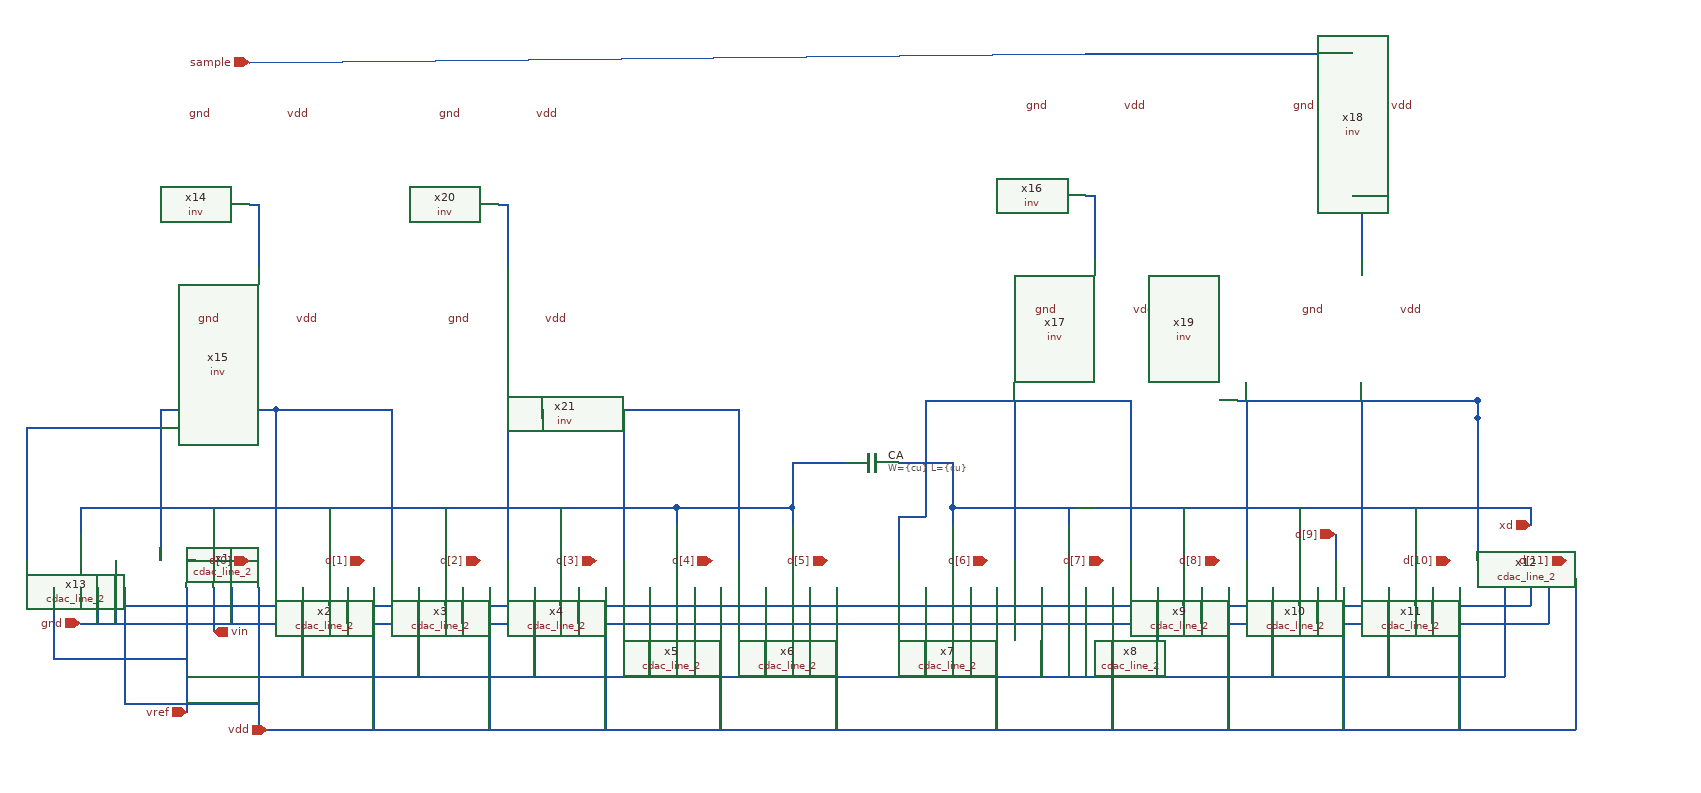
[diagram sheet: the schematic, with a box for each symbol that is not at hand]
v {xschem version=3.4.4 file_version=1.2
}
G {}
K {}
V {}
S {}
E {}
N 80 -160 80 -140 {
lab=#net1}
N -70 -160 -70 -130 {
lab=#net1}
N 50 -100 60 -100 {
lab=#net2}
N 210 -160 210 -140 {
lab=#net1}
N 340 -160 340 -140 {
lab=#net1}
N 470 -160 470 -140 {
lab=#net1}
N 600 -160 600 -140 {
lab=#net1}
N 730 -160 730 -140 {
lab=#net1}
N 910 -160 910 -140 {
lab=xd}
N 1040 -160 1040 -140 {
lab=xd}
N 1170 -160 1170 -140 {
lab=xd}
N 1300 -160 1300 -140 {
lab=xd}
N 1430 -160 1430 -140 {
lab=xd}
N 80 -70 80 -40 {
lab=vin}
N 210 -70 210 -50 {
lab=vin}
N 80 -40 80 -20 {
lab=vin}
N 230 -70 230 -30 {
lab=gnd}
N 1560 -70 1560 -50 {
lab=vin}
N 1430 -70 1430 -50 {
lab=vin}
N 1300 -70 1300 -50 {
lab=vin}
N 1170 -70 1170 -50 {
lab=vin}
N 1040 -70 1040 -50 {
lab=vin}
N 910 -70 910 -50 {
lab=vin}
N 730 -70 730 -50 {
lab=vin}
N 600 -70 600 -50 {
lab=vin}
N 470 -70 470 -50 {
lab=vin}
N 340 -70 340 -50 {
lab=vin}
N 1580 -70 1580 -30 {
lab=gnd}
N 1450 -70 1450 -30 {
lab=gnd}
N 1320 -70 1320 -30 {
lab=gnd}
N 1190 -70 1190 -30 {
lab=gnd}
N 1060 -70 1060 -30 {
lab=gnd}
N 930 -70 930 -30 {
lab=gnd}
N 750 -70 750 -30 {
lab=gnd}
N 620 -70 620 -30 {
lab=gnd}
N 490 -70 490 -30 {
lab=gnd}
N 360 -70 360 -30 {
lab=gnd}
N -70 -30 1580 -30 {
lab=gnd}
N 730 -210 730 -160 {
lab=#net1}
N 850 -210 910 -210 {
lab=xd}
N 910 -210 910 -160 {
lab=xd}
N 80 -50 1560 -50 {
lab=vin}
N 100 -70 100 -30 {
lab=gnd}
N 1040 -160 1560 -160 {
lab=xd}
N 910 -160 1050 -160 {
lab=xd}
N 50 -70 50 70 {
lab=vref}
N 180 -70 180 20 {
lab=vref}
N 310 -70 310 20 {
lab=vref}
N 440 -70 440 20 {
lab=vref}
N 570 -70 570 20 {
lab=vref}
N 700 -70 700 20 {
lab=vref}
N 880 -70 880 30 {
lab=vref}
N 1010 -70 1010 30 {
lab=vref}
N 1140 -70 1140 30 {
lab=vref}
N 1270 -70 1270 30 {
lab=vref}
N 1400 -70 1400 30 {
lab=vref}
N 1530 -70 1530 30 {
lab=vref}
N 50 30 1530 30 {
lab=vref}
N 570 20 570 30 {
lab=vref}
N 700 20 700 30 {
lab=vref}
N 440 20 440 30 {
lab=vref}
N 310 20 310 30 {
lab=vref}
N 180 20 180 30 {
lab=vref}
N 20 -270 20 -100 {
lab=#net3}
N 150 -270 150 -100 {
lab=#net3}
N 280 -270 280 -100 {
lab=#net3}
N 410 -270 410 -100 {
lab=#net4}
N 540 -270 540 -100 {
lab=#net4}
N 670 -270 670 -100 {
lab=#net4}
N 1500 -260 1500 -100 {
lab=#net5}
N 1500 -280 1500 -260 {
lab=#net5}
N 1240 -270 1240 -100 {
lab=#net5}
N 980 -270 980 -100 {
lab=#net6}
N 1110 -270 1110 -100 {
lab=#net6}
N 1370 -270 1370 -100 {
lab=#net5}
N 130 -70 130 80 {
lab=vdd}
N 1610 -80 1610 90 {
lab=vdd}
N 130 90 1610 90 {
lab=vdd}
N 130 80 130 90 {
lab=vdd}
N 260 -70 260 90 {
lab=vdd}
N 390 -70 390 90 {
lab=vdd}
N 520 -70 520 90 {
lab=vdd}
N 650 -70 650 90 {
lab=vdd}
N 780 -70 780 90 {
lab=vdd}
N 960 -70 960 90 {
lab=vdd}
N 1480 -70 1480 90 {
lab=vdd}
N 1350 -70 1350 90 {
lab=vdd}
N 1220 -70 1220 90 {
lab=vdd}
N 1090 -70 1090 90 {
lab=vdd}
N -50 -70 -50 -30 {
lab=gnd}
N -70 -70 -70 -50 {
lab=vin}
N -70 -50 80 -50 {
lab=vin}
N -100 -70 -100 10 {
lab=vref}
N -100 10 50 10 {
lab=vref}
N -20 -70 -20 60 {
lab=vdd}
N -20 60 130 60 {
lab=vdd}
N -130 -250 -130 -100 {
lab=#net3}
N -130 -250 20 -250 {
lab=#net3}
N -70 -160 600 -160 {
lab=#net1}
N 850 -150 850 -100 {
lab=#net6}
N 850 -150 880 -150 {
lab=#net6}
N 880 -270 880 -150 {
lab=#net6}
N 600 -160 730 -160 {
lab=#net1}
N 1500 -280 1500 -260 {
lab=#net5}
N 130 -500 130 -430 {
lab=#net7}
N 120 -500 130 -500 {
lab=#net7}
N 880 -280 880 -270 {
lab=#net6}
N 980 -280 980 -270 {
lab=#net6}
N 1110 -280 1110 -270 {
lab=#net6}
N 1240 -280 1240 -270 {
lab=#net5}
N 1370 -280 1370 -270 {
lab=#net5}
N 1070 -510 1070 -440 {
lab=#net8}
N 1060 -510 1070 -510 {
lab=#net8}
N 120 -660 1060 -670 {
lab=sample}
N 620 -270 670 -270 {
lab=#net4}
N 1370 -510 1370 -440 {
lab=#net9}
N 1360 -510 1370 -510 {
lab=#net9}
N 450 -270 450 -260 {
lab=#net4}
N 410 -500 410 -430 {
lab=#net10}
N 400 -500 410 -500 {
lab=#net10}
N 20 -270 150 -270 {
lab=#net3}
N 410 -270 620 -270 {
lab=#net4}
N 1230 -280 1500 -280 {
lab=#net5}
N 880 -280 1100 -280 {
lab=#net6}
N 1100 -280 1110 -280 {
lab=#net6}
N 1060 -670 1360 -670 {
lab=sample}
N 150 -270 280 -270 {
lab=#net3}
N 1340 -130 1340 -100 {
lab=d[9]}
N 1560 -160 1560 -140 {
lab=xd}
N 730 -210 790 -210 {
lab=#net1}
N -30 -100 -30 -30 {
lab=gnd}
C {cdac_line_2.sym} 80 -90 0 0 {name=x1
CW=\{sqrt(1)*cu\}
CL=\{sqrt(1)*cu\}}
C {cdac_line_2.sym} 210 -90 0 0 {name=x2
CW=\{sqrt(2)*cu\}
CL=\{sqrt(2)*cu\}}
C {cdac_line_2.sym} 340 -90 0 0 {name=x3
CW=\{sqrt(4)*cu\}
CL=\{sqrt(4)*cu\}}
C {cdac_line_2.sym} 470 -90 0 0 {name=x4
CW=\{sqrt(8)*cu\}
CL=\{sqrt(8)*cu\}}
C {cdac_line_2.sym} 600 -90 0 0 {name=x5
CW=\{sqrt(16)*cu\}
CL=\{sqrt(16)*cu\}}
C {cdac_line_2.sym} 730 -90 0 0 {name=x6
CW=\{sqrt(32)*cu\}
CL=\{sqrt(32)*cu\}}
C {symbols/cap_mim_2f0fF.sym} 820 -210 1 0 {name=CA
W=\{cu\}
L=\{cu\}
model=cap_mim_2f0fF
m=1}
C {cdac_line_2.sym} 910 -90 0 0 {name=x7
CW=\{sqrt(1)*cu\}
CL=\{sqrt(1)*cu\}}
C {cdac_line_2.sym} 1040 -90 0 0 {name=x8
CW=\{sqrt(2)*cu\}
CL=\{sqrt(2)*cu\}}
C {cdac_line_2.sym} 1170 -90 0 0 {name=x9
CW=\{sqrt(4)*cu\}
CL=\{sqrt(4)*cu\}}
C {cdac_line_2.sym} 1300 -90 0 0 {name=x10
CW=\{sqrt(8)*cu\}
CL=\{sqrt(8)*cu\}}
C {cdac_line_2.sym} 1430 -90 0 0 {name=x11
CW=\{sqrt(16)*cu\}
CL=\{sqrt(16)*cu\}}
C {cdac_line_2.sym} 1560 -90 0 0 {name=x12
CW=\{sqrt(32)*cu\}
CL=\{sqrt(32)*cu\}}
C {devices/ipin.sym} 120 -100 1 0 {name=p1 lab=d[0]}
C {devices/ipin.sym} 250 -100 1 0 {name=p2 lab=d[1]}
C {devices/ipin.sym} 380 -100 1 0 {name=p3 lab=d[2]}
C {devices/ipin.sym} 510 -100 1 0 {name=p4 lab=d[3]}
C {devices/ipin.sym} 640 -100 1 0 {name=p5 lab=d[4]}
C {devices/ipin.sym} 770 -100 1 0 {name=p6 lab=d[5]}
C {devices/ipin.sym} 950 -100 1 0 {name=p7 lab=d[6]}
C {devices/ipin.sym} 1080 -100 1 0 {name=p8 lab=d[7]}
C {devices/ipin.sym} 1210 -100 1 0 {name=p9 lab=d[8]}
C {devices/ipin.sym} 1340 -130 1 0 {name=p10 lab=d[9]}
C {devices/ipin.sym} 1470 -100 1 0 {name=p11 lab=d[10]}
C {devices/ipin.sym} 1600 -100 1 0 {name=p12 lab=d[11]}
C {devices/iopin.sym} 80 -20 3 1 {name=p13 lab=vin}
C {devices/iopin.sym} -70 -30 1 0 {name=p14 lab=gnd}
C {devices/iopin.sym} 1560 -140 0 0 {name=p16 lab=xd}
C {devices/iopin.sym} 50 70 1 0 {name=p17 lab=vref}
C {devices/iopin.sym} 140 90 1 0 {name=p18 lab=vdd}
C {cdac_line_2.sym} -70 -90 0 0 {name=x13
CW=\{sqrt(1)*cu\}
CL=\{sqrt(1)*cu\}}
C {devices/iopin.sym} 120 -660 0 0 {name=p15 lab=sample}
C {inv.sym} 120 -600 1 0 {name=x14 cl=0.28u wp=0.44u wn=0.22u wx=2u}
C {devices/lab_pin.sym} 160 -600 0 1 {name=p20 sig_type=std_logic lab=vdd}
C {devices/lab_pin.sym} 80 -600 0 0 {name=p21 sig_type=std_logic lab=gnd}
C {inv.sym} 130 -370 1 0 {name=x15 cl=0.28u wp=0.44u wn=0.22u wx=8u}
C {devices/lab_pin.sym} 170 -370 0 1 {name=p22 sig_type=std_logic lab=vdd}
C {devices/lab_pin.sym} 90 -370 0 0 {name=p23 sig_type=std_logic lab=gnd}
C {inv.sym} 1060 -610 1 0 {name=x16 cl=0.28u wp=0.44u wn=0.22u wx=2u}
C {devices/lab_pin.sym} 1100 -610 0 1 {name=p24 sig_type=std_logic lab=vdd}
C {devices/lab_pin.sym} 1020 -610 0 0 {name=p25 sig_type=std_logic lab=gnd}
C {inv.sym} 1070 -380 1 0 {name=x17 cl=0.28u wp=0.44u wn=0.22u wx=8u}
C {devices/lab_pin.sym} 1110 -380 0 1 {name=p26 sig_type=std_logic lab=vdd}
C {devices/lab_pin.sym} 1030 -380 0 0 {name=p27 sig_type=std_logic lab=gnd}
C {inv.sym} 1360 -610 1 0 {name=x18 cl=0.28u wp=0.44u wn=0.22u wx=2u}
C {devices/lab_pin.sym} 1400 -610 0 1 {name=p28 sig_type=std_logic lab=vdd}
C {devices/lab_pin.sym} 1320 -610 0 0 {name=p29 sig_type=std_logic lab=gnd}
C {inv.sym} 1370 -380 1 0 {name=x19 cl=0.28u wp=0.44u wn=0.22u wx=8u}
C {devices/lab_pin.sym} 1410 -380 0 1 {name=p30 sig_type=std_logic lab=vdd}
C {devices/lab_pin.sym} 1330 -380 0 0 {name=p31 sig_type=std_logic lab=gnd}
C {inv.sym} 400 -600 1 0 {name=x20 cl=0.28u wp=0.44u wn=0.22u wx=2u}
C {devices/lab_pin.sym} 440 -600 0 1 {name=p32 sig_type=std_logic lab=vdd}
C {devices/lab_pin.sym} 360 -600 0 0 {name=p33 sig_type=std_logic lab=gnd}
C {inv.sym} 410 -370 1 0 {name=x21 cl=0.28u wp=0.44u wn=0.22u wx=8u}
C {devices/lab_pin.sym} 450 -370 0 1 {name=p34 sig_type=std_logic lab=vdd}
C {devices/lab_pin.sym} 370 -370 0 0 {name=p35 sig_type=std_logic lab=gnd}
